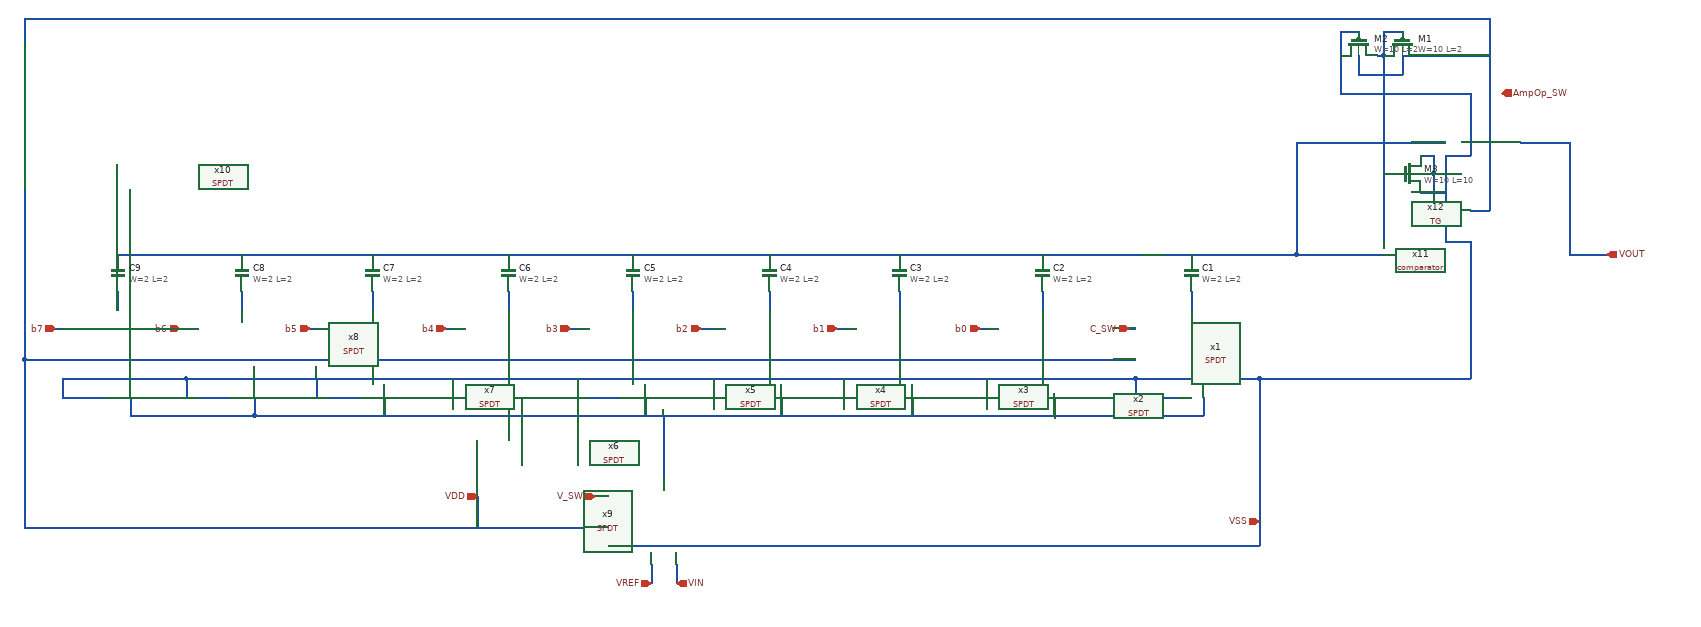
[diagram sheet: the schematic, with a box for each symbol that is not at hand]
v {xschem version=3.4.8RC file_version=1.3}
G {}
K {}
V {}
S {}
F {}
E {}
N -170 30 -170 60 {lab=#net1}
N -850 30 -850 60 {lab=#net2}
N -1070 30 -1070 60 {lab=#net3}
N -1270 30 -1270 60 {lab=#net4}
N -1490 30 -1490 60 {lab=#net5}
N -1700 30 -1700 60 {lab=#net6}
N -730 170 -730 200 {lab=VSS}
N -730 200 -660 200 {lab=VSS}
N -940 170 -940 200 {lab=VSS}
N -940 200 -870 200 {lab=VSS}
N -1160 170 -1160 200 {lab=VSS}
N -1160 200 -1090 200 {lab=VSS}
N -1360 170 -1360 200 {lab=VSS}
N -1360 200 -1290 200 {lab=VSS}
N -1580 170 -1580 200 {lab=VSS}
N -1580 200 -1510 200 {lab=VSS}
N -1790 200 -1720 200 {lab=VSS}
N -1790 170 -1790 200 {lab=VSS}
N -500 170 -500 200 {lab=VSS}
N -500 200 -430 200 {lab=VSS}
N -260 200 -190 200 {lab=VSS}
N -260 170 -260 200 {lab=VSS}
N -620 200 -620 230 {lab=#net7}
N -390 200 -390 230 {lab=#net7}
N -150 200 -150 230 {lab=#net7}
N -1680 200 -1680 230 {lab=#net7}
N -1680 230 -150 230 {lab=#net7}
N -830 200 -830 230 {lab=#net7}
N -1050 200 -1050 230 {lab=#net7}
N -1250 200 -1250 230 {lab=#net7}
N -1470 200 -1470 230 {lab=#net7}
N -1700 -30 -170 -30 {lab=#net8}
N -1850 410 -1110 410 {lab=VDD}
N -1320 360 -1320 410 {lab=VDD}
N -60 170 -60 410 {lab=VSS}
N -1110 440 -60 440 {lab=VSS}
N -60 410 -60 440 {lab=VSS}
N -1790 170 -260 170 {lab=VSS}
N -260 170 -60 170 {lab=VSS}
N -1990 170 -1990 200 {lab=VSS}
N -1990 200 -1920 200 {lab=VSS}
N -1990 170 -1790 170 {lab=VSS}
N -1880 200 -1880 230 {lab=#net7}
N -1880 230 -1680 230 {lab=#net7}
N -1900 30 -1900 60 {lab=#net9}
N -1900 -30 -1700 -30 {lab=#net8}
N -2050 140 -2050 410 {lab=VDD}
N -2050 410 -1850 410 {lab=VDD}
N -250 -30 -0 -30 {lab=#net8}
N -1020 230 -1020 330 {lab=#net7}
N -1040 470 -1040 500 {lab=VREF}
N -1000 470 -1000 500 {lab=VIN}
N -1130 360 -1110 360 {lab=V_SW}
N -270 90 -260 90 {lab=C_SW}
N -510 90 -500 90 {lab=b0}
N -740 90 -730 90 {lab=b1}
N -960 90 -940 90 {lab=b2}
N -1170 90 -1160 90 {lab=b3}
N -1370 90 -1360 90 {lab=b4}
N -1590 90 -1580 90 {lab=b5}
N -1800 90 -1790 90 {lab=b6}
N -2000 90 -1990 90 {lab=b7}
N -2050 140 -260 140 {lab=VDD}
N -410 30 -410 60 {lab=#net10}
N -640 30 -640 60 {lab=#net11}
N 360 -210 440 -210 {lab=VOUT}
N 0 -210 240 -210 {lab=#net8}
N 0 -210 -0 -30 {lab=#net8}
N -60 170 280 170 {lab=VSS}
N 440 -210 440 -30 {lab=VOUT}
N 280 40 280 170 {lab=VSS}
N 280 -50 280 40 {lab=VSS}
N 310 -290 310 -100 {lab=VDD}
N 280 -100 310 -100 {lab=VDD}
N 310 -360 310 -290 {lab=VDD}
N -2050 -370 -2050 140 {lab=VDD}
N -2050 -410 300 -410 {lab=VDD}
N 310 -370 310 -360 {lab=VDD}
N 440 -30 500 -30 {lab=VOUT}
N 140 -390 140 -350 {lab=#net12}
N 140 -390 170 -390 {lab=#net12}
N 170 -350 200 -350 {lab=VDD}
N 70 -390 100 -390 {lab=VSS}
N 70 -390 70 -350 {lab=VSS}
N 130 -350 140 -350 {lab=#net12}
N 100 -350 100 -320 {lab=VDD}
N 100 -320 170 -320 {lab=VDD}
N 170 -350 170 -320 {lab=VDD}
N 280 -290 280 -190 {lab=VSS}
N 240 -190 280 -190 {lab=VSS}
N 240 -190 240 -60 {lab=VSS}
N 240 -50 280 -50 {lab=VSS}
N 240 -60 240 -50 {lab=VSS}
N 220 -290 280 -290 {lab=VSS}
N 310 -410 310 -370 {lab=VDD}
N 300 -410 310 -410 {lab=VDD}
N -2050 -410 -2050 -360 {lab=VDD}
N 200 -350 310 -350 {lab=VDD}
N 70 -290 220 -290 {lab=VSS}
N 70 -350 70 -290 {lab=VSS}
N 0 -30 140 -30 {lab=#net8}
N 140 -350 140 -50 {lab=#net12}
N 140 -160 160 -160 {lab=#net12}
N 200 -130 240 -130 {lab=VSS}
N 200 -160 210 -160 {lab=VSS}
N 200 -190 220 -190 {lab=VSS}
N 220 -190 220 -160 {lab=VSS}
N 210 -160 220 -160 {lab=VSS}
N 220 -160 220 -130 {lab=VSS}
C {sky130_fd_pr/cap_mim_m3_1.sym} -170 0 0 0 {name=C1 model=cap_mim_m3_1 W=2 L=2 MF=1 spiceprefix=X}
C {sky130_fd_pr/cap_mim_m3_1.sym} -410 0 0 0 {name=C2 model=cap_mim_m3_1 W=2 L=2 MF=1 spiceprefix=X}
C {sky130_fd_pr/cap_mim_m3_1.sym} -640 0 0 0 {name=C3 model=cap_mim_m3_1 W=2 L=2 MF=2 spiceprefix=X}
C {sky130_fd_pr/cap_mim_m3_1.sym} -850 0 0 0 {name=C4 model=cap_mim_m3_1 W=2 L=2 MF=4 spiceprefix=X}
C {sky130_fd_pr/cap_mim_m3_1.sym} -1070 0 0 0 {name=C5 model=cap_mim_m3_1 W=2 L=2 MF=8 spiceprefix=X}
C {sky130_fd_pr/cap_mim_m3_1.sym} -1270 0 0 0 {name=C6 model=cap_mim_m3_1 W=2 L=2 MF=16 spiceprefix=X}
C {sky130_fd_pr/cap_mim_m3_1.sym} -1490 0 0 0 {name=C7 model=cap_mim_m3_1 W=2 L=2 MF=32 spiceprefix=X}
C {sky130_fd_pr/cap_mim_m3_1.sym} -1700 0 0 0 {name=C8 model=cap_mim_m3_1 W=2 L=2 MF=64 spiceprefix=X}
C {SPDT.sym} -110 130 0 0 {name=x1}
C {SPDT.sym} -350 130 0 0 {name=x2}
C {SPDT.sym} -580 130 0 0 {name=x3}
C {SPDT.sym} -790 130 0 0 {name=x4}
C {SPDT.sym} -1010 130 0 0 {name=x5}
C {SPDT.sym} -1210 130 0 0 {name=x6}
C {SPDT.sym} -1430 130 0 0 {name=x7}
C {SPDT.sym} -1640 130 0 0 {name=x8}
C {SPDT.sym} -960 400 0 0 {name=x9}
C {iopin.sym} -60 400 0 0 {name=p2 lab=VSS

}
C {iopin.sym} -1320 360 0 0 {name=p3 lab=VDD}
C {ipin.sym} -1130 360 0 0 {name=p4 lab=V_SW}
C {ipin.sym} -1800 90 0 0 {name=p5 lab=b6}
C {ipin.sym} -1590 90 0 0 {name=p6 lab=b5}
C {ipin.sym} -1370 90 0 0 {name=p7 lab=b4}
C {ipin.sym} -1170 90 0 0 {name=p8 lab=b3}
C {ipin.sym} -960 90 0 0 {name=p9 lab=b2}
C {ipin.sym} -740 90 0 0 {name=p10 lab=b1}
C {ipin.sym} -510 90 0 0 {name=p11 lab=b0}
C {ipin.sym} -270 90 0 0 {name=p12 lab=C_SW}
C {SPDT.sym} -1840 130 0 0 {name=x10}
C {sky130_fd_pr/cap_mim_m3_1.sym} -1900 0 0 0 {name=C9 model=cap_mim_m3_1 W=2 L=2 MF=128 spiceprefix=X}
C {ipin.sym} -2000 90 0 0 {name=p13 lab=b7}
C {ipin.sym} -1000 500 0 1 {name=p14 lab=VIN}
C {ipin.sym} -1040 500 0 0 {name=p15 lab=VREF}
C {comparator.sym} 290 -30 0 0 {name=x11}
C {TG.sym} 300 -140 1 0 {name=x12}
C {opin.sym} 500 -30 0 0 {name=p1 lab=VOUT}
C {ipin.sym} 330 -290 0 1 {name=p16 lab=AmpOp_SW}
C {sky130_fd_pr/pfet_01v8.sym} 170 -370 1 0 {name=M1
W=10
L=2
nf=1
mult=1
ad="expr('int((@nf + 1)/2) * @W / @nf * 0.29')"
pd="expr('2*int((@nf + 1)/2) * (@W / @nf + 0.29)')"
as="expr('int((@nf + 2)/2) * @W / @nf * 0.29')"
ps="expr('2*int((@nf + 2)/2) * (@W / @nf + 0.29)')"
nrd="expr('0.29 / @W ')" nrs="expr('0.29 / @W ')"
sa=0 sb=0 sd=0
model=pfet_01v8
spiceprefix=X
}
C {sky130_fd_pr/pfet_01v8.sym} 100 -370 1 0 {name=M2
W=10
L=2
nf=1
mult=1
ad="expr('int((@nf + 1)/2) * @W / @nf * 0.29')"
pd="expr('2*int((@nf + 1)/2) * (@W / @nf + 0.29)')"
as="expr('int((@nf + 2)/2) * @W / @nf * 0.29')"
ps="expr('2*int((@nf + 2)/2) * (@W / @nf + 0.29)')"
nrd="expr('0.29 / @W ')" nrs="expr('0.29 / @W ')"
sa=0 sb=0 sd=0
model=pfet_01v8
spiceprefix=X
}
C {sky130_fd_pr/nfet_01v8.sym} 180 -160 0 0 {name=M3
W=10
L=10
nf=1 
mult=5
ad="expr('int((@nf + 1)/2) * @W / @nf * 0.29')"
pd="expr('2*int((@nf + 1)/2) * (@W / @nf + 0.29)')"
as="expr('int((@nf + 2)/2) * @W / @nf * 0.29')"
ps="expr('2*int((@nf + 2)/2) * (@W / @nf + 0.29)')"
nrd="expr('0.29 / @W ')" nrs="expr('0.29 / @W ')"
sa=0 sb=0 sd=0
model=nfet_01v8
spiceprefix=X
}
